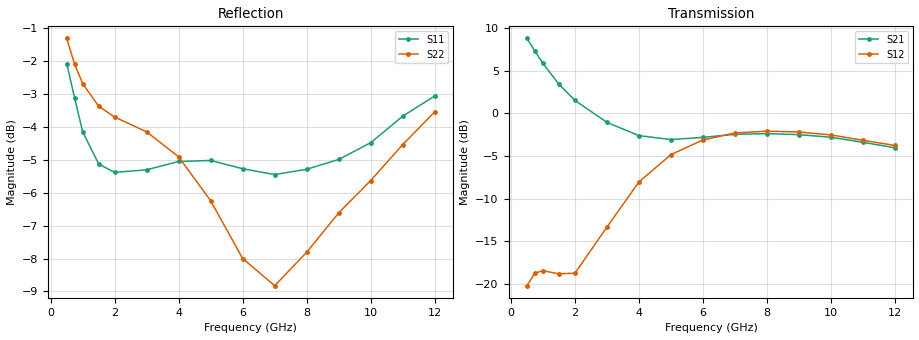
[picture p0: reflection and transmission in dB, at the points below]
!AT-41532
!S-PARAMETERS at Vce=1V  Ic=1mA.  LAST UPDATED 05-29-98
# ghz s ma r 50
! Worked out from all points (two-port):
!   15 points, 500 MHz to 12 GHz, reference 50 ohm
!   highest |S21| = 8.79 dB at 500 MHz (marker M1); lowest = -4.0 dB at 12 GHz (marker M2)
!   |S21| within 3 dB of the highest: start of sweep to 1.012 GHz
!   lowest |S11| = -5.4 dB at 7 GHz (marker M3), VSWR 3.29, Z = 144 + j51.9 ohm
!   |S11| at or under -10 dB: nowhere
!   |S22| runs from -8.8 to -1.3 dB; largest |S21 - S12| = 2.7
!   S11 on the Smith chart (normalised r, x): 500 MHz: 0.31, -1.25; 1.5 GHz: 0.29, -0.11; 3 GHz: 0.39, +0.53; 4 GHz: 0.63, +1.00; 7 GHz: 2.87, +1.04; 12 GHz: 1.13, -2.09
0.5  0.787 -75.0  2.75 125.0  0.098 49.0  0.86 -22.0
0.75  0.697 -104.0  2.311 106.0  0.116 38.0  0.785 -28.0
1  0.62 -128.0  1.96 90.0  0.12 31.0  0.734 -32.0
1.5  0.554 -166.0  1.48 66.0  0.115 30.0  0.678 -40.0
2  0.538 -164.0  1.191 48.0  0.116 42.0  0.653 -50.0
3  0.543 118.0  0.886 22.0  0.216 60.0  0.62 -73.0
4  0.559 79.0  0.741 5.0  0.397 47.0  0.568 -102.0
5  0.561 47.0  0.703 -7.0  0.574 24.0  0.487 -137.0
6  0.545 28.0  0.724 -20.0  0.699 0.0  0.398 -180.0
7  0.534 14.0  0.754 -35.0  0.768 -23.0  0.362 130.0
8  0.544 2.0  0.761 -52.0  0.787 -44.0  0.407 88.0
9  0.563 -10.0  0.751 -68.0  0.778 -63.0  0.467 58.0
10  0.597 -23.0  0.725 -84.0  0.748 -80.0  0.523 35.0
11  0.655 -34.0  0.677 -100.0  0.696 -96.0  0.593 16.0
12  0.703 -42.0  0.629 -112.0  0.649 -110.0  0.665 -6.0
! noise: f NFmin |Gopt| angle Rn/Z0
0.9  1.4  0.44  92  0.25
1.8  1.8  0.57  -183  0.06
2  1.9  0.6  -169  0.07
2.5  2.2  0.66  -140  0.2
3  2.6  0.71  -116  0.55
3.5  3.1  0.75  -95  1.2
4  3.6  0.77  -77  2.06
